VERSION 5.8 ;
BUSBITCHARS "[]" ;
DIVIDERCHAR "/" ;
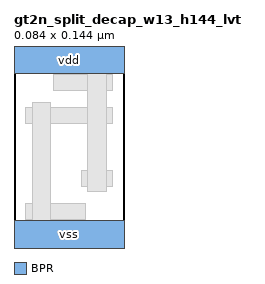
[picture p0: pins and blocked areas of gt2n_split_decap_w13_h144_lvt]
MACRO gt2n_split_decap_w13_h144_lvt
  CLASS CORE ;
  ORIGIN 0 0 ;
  SYMMETRY X Y ;
  SITE gt2_6t ;
  SIZE 0.084 BY 0.144 ;
  PIN vss
    DIRECTION INOUT ;
    USE GROUND ;
    PORT
      LAYER BPR ;
        RECT 0 -0.016 0.084 0.016 ;
    END
  END vss
  PIN vdd
    DIRECTION INOUT ;
    USE POWER ;
    PORT
      LAYER BPR ;
        RECT 0 0.128 0.084 0.16 ;
    END
  END vdd
  OBS
    LAYER M0 ;
      RECT 0.009 0.017 0.054 0.029 ;
      RECT 0.051 0.042 0.075 0.054 ;
      RECT 0.009 0.09 0.075 0.102 ;
      RECT 0.03 0.115 0.075 0.127 ;
    LAYER M1 ;
      RECT 0.014 0.013 0.028 0.106 ;
      RECT 0.056 0.038 0.07 0.131 ;
  END
END gt2n_split_decap_w13_h144_lvt
END LIBRARY
